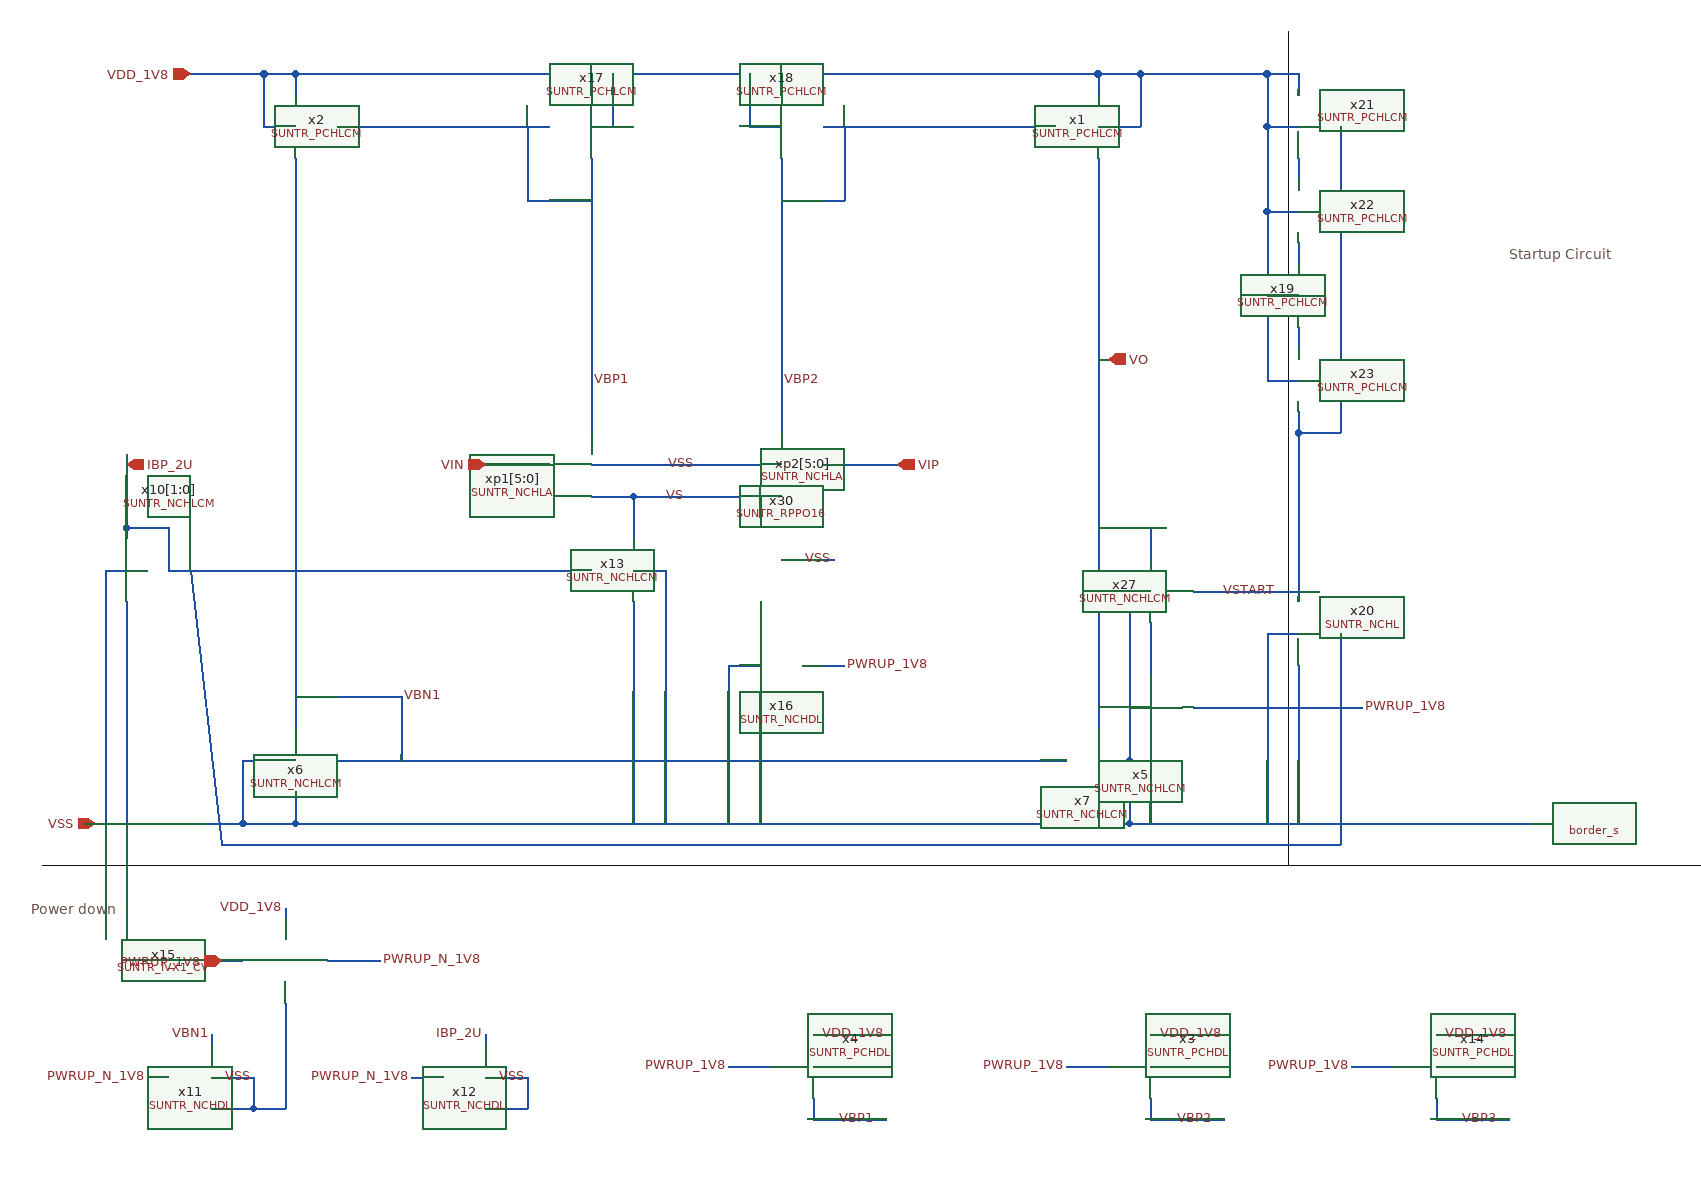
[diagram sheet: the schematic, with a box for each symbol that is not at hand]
v {xschem version=3.0.0 file_version=1.2 }
G {}
K {}
V {}
S {}
E {}
L 3 -810 -590 840 -590 {}
L 3 370 -1380 370 -590 {}
T {Power down } -820 -560 0 0 0.4 0.4 {}
T {Startup Circuit} 580 -1180 0 0 0.4 0.4 {}
N -290 -630 190 -630 {
lab=VSS}
N 190 -660 190 -630 {
lab=VSS}
N -570 -660 -570 -630 {
lab=VSS}
N -570 -630 -290 -630 {
lab=VSS}
N -620 -690 -570 -690 {
lab=VSS}
N -620 -690 -620 -630 {
lab=VSS}
N -620 -630 -570 -630 {
lab=VSS}
N -460 -390 -430 -390 {
lab=PWRUP_N_1V8}
N -710 -390 -690 -390 {
lab=PWRUP_N_1V8}
N -290 -1020 -290 -1000 {
lab=VBP1}
N -110 -1020 -110 -1000 {
lab=VBP2}
N -290 -970 -110 -970 {
lab=VSS}
N -570 -1260 -570 -720 {
lab=VBN1}
N -570 -1340 -570 -1320 {
lab=VDD_1V8}
N -570 -1340 190 -1340 {
lab=VDD_1V8}
N 190 -1340 190 -1320 {
lab=VDD_1V8}
N 190 -1290 230 -1290 {
lab=VDD_1V8}
N 230 -1340 230 -1290 {
lab=VDD_1V8}
N 190 -1340 230 -1340 {
lab=VDD_1V8}
N -600 -1290 -570 -1290 {
lab=VDD_1V8}
N -600 -1340 -600 -1290 {
lab=VDD_1V8}
N -600 -1340 -570 -1340 {
lab=VDD_1V8}
N 190 -1260 190 -1240 {
lab=VO}
N -80 -400 -10 -400 {
lab=VDD_1V8}
N -80 -430 -10 -430 {
lab=VDD_1V8}
N -10 -430 -10 -400 {
lab=VDD_1V8}
N 190 -1240 190 -720 {
lab=VO}
N -160 -400 -120 -400 {
lab=PWRUP_1V8}
N -670 -1340 -600 -1340 {
lab=VDD_1V8}
N 190 -1070 200 -1070 {
lab=VO}
N 190 -690 220 -690 {
lab=VSS}
N 220 -690 220 -630 {
lab=VSS}
N -770 -630 -620 -630 {
lab=VSS}
N -540 -500 -490 -500 {
lab=PWRUP_N_1V8}
N -650 -500 -620 -500 {
lab=PWRUP_1V8}
N -360 -970 -330 -970 {
lab=VIN}
N 190 -630 220 -630 {
lab=VSS}
N -650 -430 -650 -420 {
lab=VBN1}
N -390 -430 -390 -420 {
lab=IBP_2U}
N -650 -390 -610 -390 {
lab=VSS}
N -610 -390 -610 -360 {
lab=VSS}
N -650 -360 -610 -360 {
lab=VSS}
N -390 -390 -350 -390 {
lab=VSS}
N -350 -390 -350 -360 {
lab=VSS}
N -390 -360 -350 -360 {
lab=VSS}
N -80 -370 -80 -350 {
lab=VBP1}
N -80 -350 -10 -350 {
lab=VBP1}
N -400 -970 -370 -970 {
lab=VIN}
N -370 -970 -360 -970 {
lab=VIN}
N -30 -970 0 -970 {
lab=VIP}
N 240 -400 310 -400 {
lab=VDD_1V8}
N 240 -430 310 -430 {
lab=VDD_1V8}
N 310 -430 310 -400 {
lab=VDD_1V8}
N 160 -400 200 -400 {
lab=PWRUP_1V8}
N 240 -370 240 -350 {
lab=VBP2}
N 240 -350 310 -350 {
lab=VBP2}
N 270 -630 370 -630 {
lab=VSS}
N 220 -630 270 -630 {
lab=VSS}
N -70 -970 -30 -970 {
lab=VIP}
N -110 -880 -60 -880 {
lab=VSS}
N 370 -630 570 -630 {
lab=VSS}
N 570 -630 600 -630 {
lab=VSS}
N 510 -400 580 -400 {
lab=VDD_1V8}
N 510 -430 580 -430 {
lab=VDD_1V8}
N 580 -430 580 -400 {
lab=VDD_1V8}
N 430 -400 470 -400 {
lab=PWRUP_1V8}
N 510 -370 510 -350 {
lab=VBP3}
N 510 -350 580 -350 {
lab=VBP3}
N -130 -840 -130 -820 {
lab=#net1}
N -580 -550 -580 -540 {
lab=VDD_1V8}
N -580 -460 -580 -360 {
lab=VSS}
N -610 -360 -580 -360 {
lab=VSS}
N -730 -840 -730 -630 {
lab=VSS}
N -750 -870 -730 -870 {
lab=VSS}
N -750 -870 -750 -630 {
lab=VSS}
N -690 -910 -690 -870 {
lab=IBP_2U}
N -730 -910 -690 -910 {
lab=IBP_2U}
N -730 -910 -730 -900 {
lab=IBP_2U}
N -730 -980 -730 -910 {
lab=IBP_2U}
N -690 -870 -290 -870 {
lab=IBP_2U}
N -250 -840 -250 -630 {
lab=VSS}
N -250 -870 -220 -870 {
lab=VSS}
N -220 -870 -220 -630 {
lab=VSS}
N -250 -940 -250 -900 {
lab=VS}
N -290 -940 -250 -940 {
lab=VS}
N -250 -940 -110 -940 {
lab=VS}
N -130 -940 -130 -920 {
lab=VS}
N -130 -820 -130 -810 {
lab=#net1}
N -160 -780 -130 -780 {
lab=VSS}
N -160 -780 -160 -630 {
lab=VSS}
N -130 -750 -130 -630 {
lab=VSS}
N -90 -780 -50 -780 {
lab=PWRUP_1V8}
N -290 -1260 -290 -1020 {
lab=VBP1}
N -110 -1260 -110 -1020 {
lab=VBP2}
N -140 -1290 -110 -1290 {
lab=VDD_1V8}
N -140 -1340 -140 -1290 {
lab=VDD_1V8}
N -110 -1340 -110 -1320 {
lab=VDD_1V8}
N -290 -1340 -290 -1320 {
lab=VDD_1V8}
N -290 -1290 -270 -1290 {
lab=VDD_1V8}
N -270 -1340 -270 -1290 {
lab=VDD_1V8}
N -530 -1290 -330 -1290 {
lab=VBP1}
N -350 -1290 -350 -1220 {
lab=VBP1}
N -350 -1220 -290 -1220 {
lab=VBP1}
N -70 -1290 150 -1290 {
lab=VBP2}
N -110 -1220 -50 -1220 {
lab=VBP2}
N -50 -1290 -50 -1220 {
lab=VBP2}
N -530 -690 160 -690 {
lab=VBN1}
N -570 -750 -470 -750 {
lab=VBN1}
N -470 -750 -470 -690 {
lab=VBN1}
N 350 -810 380 -810 {
lab=VSS}
N 350 -810 350 -630 {
lab=VSS}
N 380 -780 380 -630 {
lab=VSS}
N 350 -1290 380 -1290 {
lab=VDD_1V8}
N 350 -1340 350 -1290 {
lab=VDD_1V8}
N 380 -1340 380 -1320 {
lab=VDD_1V8}
N 380 -1180 380 -1160 {
lab=#net2}
N 380 -1260 380 -1240 {
lab=#net3}
N 350 -1210 380 -1210 {
lab=VDD_1V8}
N 350 -1290 350 -1210 {
lab=VDD_1V8}
N 380 -860 380 -840 {
lab=VSTART}
N 340 -850 380 -850 {
lab=VSTART}
N 220 -850 240 -850 {
lab=VSS}
N 220 -850 220 -690 {
lab=VSS}
N 240 -910 240 -880 {
lab=VO}
N 190 -910 240 -910 {
lab=VO}
N 280 -850 340 -850 {
lab=VSTART}
N -670 -870 -640 -610 {
lab=IBP_2U}
N 420 -1290 420 -1250 {
lab=VSTART}
N 420 -1210 420 -1160 {
lab=VSTART}
N 420 -810 420 -610 {
lab=IBP_2U}
N 420 -1250 420 -1210 {
lab=VSTART}
N 420 -1130 420 -1050 {
lab=VSTART}
N 420 -1160 420 -1130 {
lab=VSTART}
N 380 -1100 380 -1080 {
lab=#net5}
N 350 -1050 380 -1050 {
lab=VDD_1V8}
N 350 -1210 350 -1050 {
lab=VDD_1V8}
N 350 -1130 380 -1130 {
lab=VDD_1V8}
N 420 -1050 420 -1000 {
lab=VSTART}
N 380 -1000 420 -1000 {
lab=VSTART}
N 380 -1020 380 -1000 {
lab=VSTART}
N 380 -1000 380 -860 {
lab=VSTART}
N 240 -820 240 -770 {
lab=#net6}
N 220 -740 240 -740 {
lab=VSS}
N 240 -710 240 -630 {
lab=VSS}
N 280 -740 440 -740 {}
N 350 -1340 380 -1340 {}
N 230 -1340 350 -1340 {}
N -640 -610 420 -610 {}
C {cborder/border_s.sym} 400 -480 0 0 {}
C {SUN_TR_SKY130NM/SUNTR_PCHLCM.sym} 150 -1290 0 0 {name=x1  }
C {SUN_TR_SKY130NM/SUNTR_PCHLCM.sym} -530 -1290 0 1 {name=x2 }
C {SUN_TR_SKY130NM/SUNTR_PCHDL.sym} -120 -400 0 0 {name=x4  }
C {SUN_TR_SKY130NM/SUNTR_NCHLCM.sym} 150 -690 0 0 {name=x7  }
C {SUN_TR_SKY130NM/SUNTR_NCHLCM.sym} -530 -690 0 1 {name=x6  }
C {SUN_TR_SKY130NM/SUNTR_NCHDL.sym} -690 -390 0 0 {name=x11  }
C {SUN_TR_SKY130NM/SUNTR_NCHDL.sym} -430 -390 0 0 {name=x12  }
C {SUN_TR_SKY130NM/SUNTR_NCHLA.sym} -330 -970 0 0 {name=xp1[5:0] }
C {SUN_TR_SKY130NM/SUNTR_NCHLA.sym} -70 -970 0 1 {name=xp2[5:0] }
C {devices/ipin.sym} -670 -1340 0 0 {name=p1 lab=VDD_1V8}
C {devices/lab_pin.sym} -470 -750 0 1 {name=l2 sig_type=std_logic lab=VBN1}
C {devices/opin.sym} 200 -1070 0 0 {name=p2 lab=VO}
C {devices/lab_pin.sym} -160 -400 0 0 {name=l5 sig_type=std_logic lab=PWRUP_1V8}
C {devices/lab_pin.sym} -290 -1050 0 1 {name=l6 sig_type=std_logic lab=VBP1}
C {devices/lab_pin.sym} -110 -1050 0 1 {name=l7 sig_type=std_logic lab=VBP2}
C {devices/ipin.sym} -760 -630 0 0 {name=p3 lab=VSS}
C {SUN_TR_SKY130NM/SUNTR_IVX1_CV.sym} -620 -500 0 0 {name=x15  }
C {devices/ipin.sym} -640 -500 0 0 {name=p4 lab=PWRUP_1V8}
C {devices/lab_pin.sym} -490 -500 0 1 {name=l12 sig_type=std_logic lab=PWRUP_N_1V8}
C {devices/ipin.sym} -390 -970 0 0 {name=p5 lab=VIN}
C {devices/ipin.sym} 0 -970 0 1 {name=p6 lab=VIP}
C {devices/lab_wire.sym} -610 -390 0 0 {name=l3 sig_type=std_logic lab=VSS}
C {devices/lab_wire.sym} -710 -390 0 0 {name=l4 sig_type=std_logic lab=PWRUP_N_1V8}
C {devices/lab_wire.sym} -460 -390 0 0 {name=l18 sig_type=std_logic lab=PWRUP_N_1V8}
C {devices/lab_wire.sym} -650 -430 0 0 {name=l19 sig_type=std_logic lab=VBN1}
C {devices/lab_wire.sym} -390 -430 0 0 {name=l20 sig_type=std_logic lab=IBP_2U}
C {devices/lab_wire.sym} -350 -390 0 0 {name=l21 sig_type=std_logic lab=VSS}
C {devices/lab_wire.sym} -10 -430 0 0 {name=l22 sig_type=std_logic lab=VDD_1V8}
C {devices/lab_wire.sym} -20 -350 0 0 {name=l23 sig_type=std_logic lab=VBP1}
C {devices/lab_wire.sym} -190 -970 0 0 {name=l24 sig_type=std_logic lab=VSS}
C {SUN_TR_SKY130NM/SUNTR_PCHDL.sym} 200 -400 0 0 {name=x3  }
C {devices/lab_pin.sym} 160 -400 0 0 {name=l31 sig_type=std_logic lab=PWRUP_1V8}
C {devices/lab_wire.sym} 310 -430 0 0 {name=l32 sig_type=std_logic lab=VDD_1V8}
C {devices/lab_wire.sym} 300 -350 0 0 {name=l33 sig_type=std_logic lab=VBP2}
C {devices/ipin.sym} -730 -970 3 1 {name=p7 lab=IBP_2U}
C {SUN_TR_SKY130NM/SUNTR_RPPO16.sym} -130 -920 3 1 {name=x30  }
C {devices/lab_wire.sym} -60 -880 0 0 {name=l37 sig_type=std_logic lab=VSS}
C {devices/lab_wire.sym} -580 -550 0 0 {name=l1 sig_type=std_logic lab=VDD_1V8}
C {devices/lab_pin.sym} 440 -740 0 1 {name=l8 sig_type=std_logic lab=PWRUP_1V8}
C {SUN_TR_SKY130NM/SUNTR_PCHDL.sym} 470 -400 0 0 {name=x14  }
C {devices/lab_pin.sym} 430 -400 0 0 {name=l10 sig_type=std_logic lab=PWRUP_1V8}
C {devices/lab_wire.sym} 580 -430 0 0 {name=l11 sig_type=std_logic lab=VDD_1V8}
C {devices/lab_wire.sym} 570 -350 0 0 {name=l14 sig_type=std_logic lab=VBP3}
C {SUN_TR_SKY130NM/SUNTR_NCHLCM.sym} -690 -870 0 1 {name=x10[1:0]}
C {SUN_TR_SKY130NM/SUNTR_NCHLCM.sym} -290 -870 0 0 {name=x13}
C {SUN_TR_SKY130NM/SUNTR_NCHDL.sym} -90 -780 0 1 {name=x16  }
C {devices/lab_pin.sym} -50 -780 0 1 {name=l13 sig_type=std_logic lab=PWRUP_1V8}
C {SUN_TR_SKY130NM/SUNTR_PCHLCM.sym} -330 -1290 0 0 {name=x17 }
C {SUN_TR_SKY130NM/SUNTR_PCHLCM.sym} -70 -1290 0 1 {name=x18 }
C {devices/lab_wire.sym} -200 -940 0 0 {name=l15 sig_type=std_logic lab=VS}
C {SUN_TR_SKY130NM/SUNTR_NCHL.sym} 420 -810 0 1 {name=x20  }
C {SUN_TR_SKY130NM/SUNTR_PCHLCM.sym} 420 -1290 0 1 {name=x21  }
C {SUN_TR_SKY130NM/SUNTR_PCHLCM.sym} 420 -1210 0 1 {name=x22  }
C {SUN_TR_SKY130NM/SUNTR_NCHLCM.sym} 280 -850 0 1 {name=x27  }
C {devices/lab_wire.sym} 360 -850 0 0 {name=l16 sig_type=std_logic lab=VSTART}
C {SUN_TR_SKY130NM/SUNTR_PCHLCM.sym} 420 -1130 0 1 {name=x19  }
C {SUN_TR_SKY130NM/SUNTR_PCHLCM.sym} 420 -1050 0 1 {name=x23  }
C {SUN_TR_SKY130NM/SUNTR_NCHLCM.sym} 280 -740 0 1 {name=x5  }
